# i3dPDK_A16K 4-track technology LEF (1x), derived from TECH/i3dPDK_A16K_0V7_27C_4T_mw.tf
# i3dPDK_A16K v1.0 (CC BY-NC-SA 4.0, Prof. Taigon Song, I3D VLSI Lab, KNU)
# NOT part of the original PDK. Routing directions, wire R/C and via resistance
# are placeholders (see platform/README.md).
VERSION 5.8 ;
BUSBITCHARS "[]" ;
DIVIDERCHAR "/" ;

UNITS
  DATABASE MICRONS 2000 ;
END UNITS
MANUFACTURINGGRID 0.0005 ;

# Unidirectional variant: M1 M2 M3 preferred direction only, on track (RIGHTWAYONGRIDONLY + RECTONLY).
PROPERTYDEFINITIONS
  LAYER LEF58_RIGHTWAYONGRIDONLY STRING ;
  LAYER LEF58_RECTONLY STRING ;
END PROPERTYDEFINITIONS

SITE i3d_16A
  CLASS CORE ;
  SYMMETRY Y ;
  SIZE 0.042 BY 0.072 ;
END i3d_16A

SITE i3d_16A_2H_VDD
  CLASS CORE ;
  SYMMETRY Y ;
  SIZE 0.042 BY 0.144 ;
END i3d_16A_2H_VDD

SITE i3d_16A_2H_VSS
  CLASS CORE ;
  SYMMETRY Y ;
  SIZE 0.042 BY 0.144 ;
END i3d_16A_2H_VSS

SITE i3d_16A_3H_VDD
  CLASS CORE ;
  SYMMETRY Y ;
  SIZE 0.042 BY 0.216 ;
END i3d_16A_3H_VDD

SITE i3d_16A_3H_VSS
  CLASS CORE ;
  SYMMETRY Y ;
  SIZE 0.042 BY 0.216 ;
END i3d_16A_3H_VSS

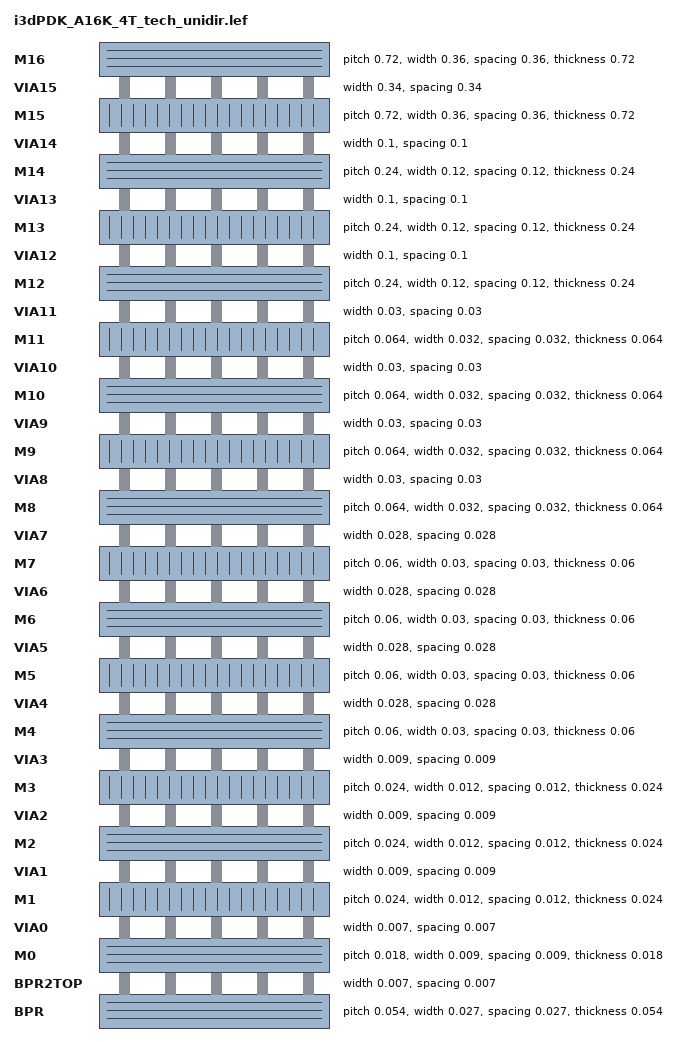
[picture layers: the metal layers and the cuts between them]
LAYER BPR
  TYPE ROUTING ;
  DIRECTION HORIZONTAL ;
  PITCH 0.054 ;
  OFFSET 0.027 ;
  WIDTH 0.027 ;
  MINWIDTH 0.027 ;
  HEIGHT 0 ;
  THICKNESS 0.054 ;
  MAXWIDTH 5 ;
  SPACING 0.027 ;
  AREA 0.003132 ;
  RESISTANCE RPERSQ 1.0000 ;
  CAPACITANCE CPERSQDIST 0.00200000 ;
  EDGECAPACITANCE 0.00008000 ;
END BPR

LAYER BPR2TOP
  TYPE CUT ;
  WIDTH 0.007 ;
  SPACING 0.007 ;
  RESISTANCE 20.0000 ;
END BPR2TOP

LAYER M0
  TYPE ROUTING ;
  DIRECTION HORIZONTAL ;
  PITCH 0.018 ;
  OFFSET 0.009 ;
  WIDTH 0.009 ;
  MINWIDTH 0.009 ;
  HEIGHT 0.108 ;
  THICKNESS 0.018 ;
  MAXWIDTH 5 ;
  SPACING 0.009 ;
  AREA 0.000081 ;
  RESISTANCE RPERSQ 8.0000 ;
  CAPACITANCE CPERSQDIST 0.00300000 ;
  EDGECAPACITANCE 0.00008000 ;
END M0

LAYER VIA0
  TYPE CUT ;
  WIDTH 0.007 ;
  SPACING 0.007 ;
  RESISTANCE 50.0000 ;
END VIA0

LAYER M1
  TYPE ROUTING ;
  DIRECTION VERTICAL ;
  PITCH 0.024 ;
  OFFSET 0 ;
  WIDTH 0.012 ;
  MINWIDTH 0.012 ;
  HEIGHT 0.144 ;
  THICKNESS 0.024 ;
  MAXWIDTH 5 ;
  SPACING 0.012 ;
  AREA 0.000144 ;
  RESISTANCE RPERSQ 8.0000 ;
  CAPACITANCE CPERSQDIST 0.00300000 ;
  EDGECAPACITANCE 0.00008000 ;
  PROPERTY LEF58_RIGHTWAYONGRIDONLY "RIGHTWAYONGRIDONLY ;" ;
  PROPERTY LEF58_RECTONLY "RECTONLY ;" ;
END M1

LAYER VIA1
  TYPE CUT ;
  WIDTH 0.009 ;
  SPACING 0.009 ;
  RESISTANCE 50.0000 ;
END VIA1

LAYER M2
  TYPE ROUTING ;
  DIRECTION HORIZONTAL ;
  PITCH 0.024 ;
  OFFSET 0 ;
  WIDTH 0.012 ;
  MINWIDTH 0.012 ;
  HEIGHT 0.192 ;
  THICKNESS 0.024 ;
  MAXWIDTH 5 ;
  SPACING 0.012 ;
  AREA 0.000144 ;
  RESISTANCE RPERSQ 8.0000 ;
  CAPACITANCE CPERSQDIST 0.00300000 ;
  EDGECAPACITANCE 0.00008000 ;
  PROPERTY LEF58_RIGHTWAYONGRIDONLY "RIGHTWAYONGRIDONLY ;" ;
  PROPERTY LEF58_RECTONLY "RECTONLY ;" ;
END M2

LAYER VIA2
  TYPE CUT ;
  WIDTH 0.009 ;
  SPACING 0.009 ;
  RESISTANCE 50.0000 ;
END VIA2

LAYER M3
  TYPE ROUTING ;
  DIRECTION VERTICAL ;
  PITCH 0.024 ;
  OFFSET 0 ;
  WIDTH 0.012 ;
  MINWIDTH 0.012 ;
  HEIGHT 0.24 ;
  THICKNESS 0.024 ;
  MAXWIDTH 5 ;
  SPACING 0.012 ;
  AREA 0.000144 ;
  RESISTANCE RPERSQ 8.0000 ;
  CAPACITANCE CPERSQDIST 0.00300000 ;
  EDGECAPACITANCE 0.00008000 ;
  PROPERTY LEF58_RIGHTWAYONGRIDONLY "RIGHTWAYONGRIDONLY ;" ;
  PROPERTY LEF58_RECTONLY "RECTONLY ;" ;
END M3

LAYER VIA3
  TYPE CUT ;
  WIDTH 0.009 ;
  SPACING 0.009 ;
  RESISTANCE 50.0000 ;
END VIA3

LAYER M4
  TYPE ROUTING ;
  DIRECTION HORIZONTAL ;
  PITCH 0.06 ;
  OFFSET 0.03 ;
  WIDTH 0.03 ;
  MINWIDTH 0.03 ;
  HEIGHT 0.288 ;
  THICKNESS 0.06 ;
  MAXWIDTH 5 ;
  SPACING 0.03 ;
  AREA 0.000900 ;
  RESISTANCE RPERSQ 1.2000 ;
  CAPACITANCE CPERSQDIST 0.00200000 ;
  EDGECAPACITANCE 0.00007000 ;
END M4

LAYER VIA4
  TYPE CUT ;
  WIDTH 0.028 ;
  SPACING 0.028 ;
  RESISTANCE 15.0000 ;
END VIA4

LAYER M5
  TYPE ROUTING ;
  DIRECTION VERTICAL ;
  PITCH 0.06 ;
  OFFSET 0.03 ;
  WIDTH 0.03 ;
  MINWIDTH 0.03 ;
  HEIGHT 0.408 ;
  THICKNESS 0.06 ;
  MAXWIDTH 5 ;
  SPACING 0.03 ;
  AREA 0.000900 ;
  RESISTANCE RPERSQ 1.2000 ;
  CAPACITANCE CPERSQDIST 0.00200000 ;
  EDGECAPACITANCE 0.00007000 ;
END M5

LAYER VIA5
  TYPE CUT ;
  WIDTH 0.028 ;
  SPACING 0.028 ;
  RESISTANCE 15.0000 ;
END VIA5

LAYER M6
  TYPE ROUTING ;
  DIRECTION HORIZONTAL ;
  PITCH 0.06 ;
  OFFSET 0.03 ;
  WIDTH 0.03 ;
  MINWIDTH 0.03 ;
  HEIGHT 0.528 ;
  THICKNESS 0.06 ;
  MAXWIDTH 5 ;
  SPACING 0.03 ;
  AREA 0.000900 ;
  RESISTANCE RPERSQ 1.2000 ;
  CAPACITANCE CPERSQDIST 0.00200000 ;
  EDGECAPACITANCE 0.00007000 ;
END M6

LAYER VIA6
  TYPE CUT ;
  WIDTH 0.028 ;
  SPACING 0.028 ;
  RESISTANCE 15.0000 ;
END VIA6

LAYER M7
  TYPE ROUTING ;
  DIRECTION VERTICAL ;
  PITCH 0.06 ;
  OFFSET 0.03 ;
  WIDTH 0.03 ;
  MINWIDTH 0.03 ;
  HEIGHT 0.648 ;
  THICKNESS 0.06 ;
  MAXWIDTH 5 ;
  SPACING 0.03 ;
  AREA 0.000900 ;
  RESISTANCE RPERSQ 1.2000 ;
  CAPACITANCE CPERSQDIST 0.00200000 ;
  EDGECAPACITANCE 0.00007000 ;
END M7

LAYER VIA7
  TYPE CUT ;
  WIDTH 0.028 ;
  SPACING 0.028 ;
  RESISTANCE 15.0000 ;
END VIA7

LAYER M8
  TYPE ROUTING ;
  DIRECTION HORIZONTAL ;
  PITCH 0.064 ;
  OFFSET 0.032 ;
  WIDTH 0.032 ;
  MINWIDTH 0.032 ;
  HEIGHT 0.768 ;
  THICKNESS 0.064 ;
  MAXWIDTH 5 ;
  SPACING 0.032 ;
  AREA 0.001024 ;
  RESISTANCE RPERSQ 1.0000 ;
  CAPACITANCE CPERSQDIST 0.00200000 ;
  EDGECAPACITANCE 0.00007000 ;
END M8

LAYER VIA8
  TYPE CUT ;
  WIDTH 0.03 ;
  SPACING 0.03 ;
  RESISTANCE 10.0000 ;
END VIA8

LAYER M9
  TYPE ROUTING ;
  DIRECTION VERTICAL ;
  PITCH 0.064 ;
  OFFSET 0.032 ;
  WIDTH 0.032 ;
  MINWIDTH 0.032 ;
  HEIGHT 0.896 ;
  THICKNESS 0.064 ;
  MAXWIDTH 5 ;
  SPACING 0.032 ;
  AREA 0.001024 ;
  RESISTANCE RPERSQ 1.0000 ;
  CAPACITANCE CPERSQDIST 0.00200000 ;
  EDGECAPACITANCE 0.00007000 ;
END M9

LAYER VIA9
  TYPE CUT ;
  WIDTH 0.03 ;
  SPACING 0.03 ;
  RESISTANCE 10.0000 ;
END VIA9

LAYER M10
  TYPE ROUTING ;
  DIRECTION HORIZONTAL ;
  PITCH 0.064 ;
  OFFSET 0.032 ;
  WIDTH 0.032 ;
  MINWIDTH 0.032 ;
  HEIGHT 1.024 ;
  THICKNESS 0.064 ;
  MAXWIDTH 5 ;
  SPACING 0.032 ;
  AREA 0.001024 ;
  RESISTANCE RPERSQ 1.0000 ;
  CAPACITANCE CPERSQDIST 0.00200000 ;
  EDGECAPACITANCE 0.00007000 ;
END M10

LAYER VIA10
  TYPE CUT ;
  WIDTH 0.03 ;
  SPACING 0.03 ;
  RESISTANCE 10.0000 ;
END VIA10

LAYER M11
  TYPE ROUTING ;
  DIRECTION VERTICAL ;
  PITCH 0.064 ;
  OFFSET 0.032 ;
  WIDTH 0.032 ;
  MINWIDTH 0.032 ;
  HEIGHT 1.152 ;
  THICKNESS 0.064 ;
  MAXWIDTH 5 ;
  SPACING 0.032 ;
  AREA 0.001024 ;
  RESISTANCE RPERSQ 1.0000 ;
  CAPACITANCE CPERSQDIST 0.00200000 ;
  EDGECAPACITANCE 0.00007000 ;
END M11

LAYER VIA11
  TYPE CUT ;
  WIDTH 0.03 ;
  SPACING 0.03 ;
  RESISTANCE 10.0000 ;
END VIA11

LAYER M12
  TYPE ROUTING ;
  DIRECTION HORIZONTAL ;
  PITCH 0.24 ;
  OFFSET 0.12 ;
  WIDTH 0.12 ;
  MINWIDTH 0.12 ;
  HEIGHT 1.28 ;
  THICKNESS 0.24 ;
  MAXWIDTH 5 ;
  SPACING 0.12 ;
  AREA 0.014400 ;
  RESISTANCE RPERSQ 0.1000 ;
  CAPACITANCE CPERSQDIST 0.00100000 ;
  EDGECAPACITANCE 0.00006000 ;
END M12

LAYER VIA12
  TYPE CUT ;
  WIDTH 0.1 ;
  SPACING 0.1 ;
  RESISTANCE 2.0000 ;
END VIA12

LAYER M13
  TYPE ROUTING ;
  DIRECTION VERTICAL ;
  PITCH 0.24 ;
  OFFSET 0.12 ;
  WIDTH 0.12 ;
  MINWIDTH 0.12 ;
  HEIGHT 1.76 ;
  THICKNESS 0.24 ;
  MAXWIDTH 5 ;
  SPACING 0.12 ;
  AREA 0.014400 ;
  RESISTANCE RPERSQ 0.1000 ;
  CAPACITANCE CPERSQDIST 0.00100000 ;
  EDGECAPACITANCE 0.00006000 ;
END M13

LAYER VIA13
  TYPE CUT ;
  WIDTH 0.1 ;
  SPACING 0.1 ;
  RESISTANCE 2.0000 ;
END VIA13

LAYER M14
  TYPE ROUTING ;
  DIRECTION HORIZONTAL ;
  PITCH 0.24 ;
  OFFSET 0.12 ;
  WIDTH 0.12 ;
  MINWIDTH 0.12 ;
  HEIGHT 2.24 ;
  THICKNESS 0.24 ;
  MAXWIDTH 5 ;
  SPACING 0.12 ;
  AREA 0.014400 ;
  RESISTANCE RPERSQ 0.1000 ;
  CAPACITANCE CPERSQDIST 0.00100000 ;
  EDGECAPACITANCE 0.00006000 ;
END M14

LAYER VIA14
  TYPE CUT ;
  WIDTH 0.1 ;
  SPACING 0.1 ;
  RESISTANCE 2.0000 ;
END VIA14

LAYER M15
  TYPE ROUTING ;
  DIRECTION VERTICAL ;
  PITCH 0.72 ;
  OFFSET 0.36 ;
  WIDTH 0.36 ;
  MINWIDTH 0.36 ;
  HEIGHT 2.72 ;
  THICKNESS 0.72 ;
  MAXWIDTH 5 ;
  SPACING 0.36 ;
  AREA 0.129600 ;
  RESISTANCE RPERSQ 0.0300 ;
  CAPACITANCE CPERSQDIST 0.00050000 ;
  EDGECAPACITANCE 0.00005000 ;
END M15

LAYER VIA15
  TYPE CUT ;
  WIDTH 0.34 ;
  SPACING 0.34 ;
  RESISTANCE 0.5000 ;
END VIA15

LAYER M16
  TYPE ROUTING ;
  DIRECTION HORIZONTAL ;
  PITCH 0.72 ;
  OFFSET 0.36 ;
  WIDTH 0.36 ;
  MINWIDTH 0.36 ;
  HEIGHT 4.16 ;
  THICKNESS 0.72 ;
  MAXWIDTH 5 ;
  SPACING 0.36 ;
  AREA 0.129600 ;
  RESISTANCE RPERSQ 0.0300 ;
  CAPACITANCE CPERSQDIST 0.00050000 ;
  EDGECAPACITANCE 0.00005000 ;
END M16

VIA viaBPR0 DEFAULT
  RESISTANCE 20.0000 ;
  LAYER BPR ;
    RECT -0.0135 -0.0135 0.0135 0.0135 ;
  LAYER BPR2TOP ;
    RECT -0.0035 -0.0035 0.0035 0.0035 ;
  LAYER M0 ;
    RECT -0.0045 -0.0045 0.0045 0.0045 ;
END viaBPR0

VIA via01 DEFAULT
  RESISTANCE 50.0000 ;
  LAYER M0 ;
    RECT -0.0045 -0.0045 0.0045 0.0045 ;
  LAYER VIA0 ;
    RECT -0.0035 -0.0035 0.0035 0.0035 ;
  LAYER M1 ;
    RECT -0.006 -0.006 0.006 0.006 ;
END via01

VIA via12 DEFAULT
  RESISTANCE 50.0000 ;
  LAYER M1 ;
    RECT -0.006 -0.006 0.006 0.006 ;
  LAYER VIA1 ;
    RECT -0.0045 -0.0045 0.0045 0.0045 ;
  LAYER M2 ;
    RECT -0.006 -0.006 0.006 0.006 ;
END via12

VIA via23 DEFAULT
  RESISTANCE 50.0000 ;
  LAYER M2 ;
    RECT -0.006 -0.006 0.006 0.006 ;
  LAYER VIA2 ;
    RECT -0.0045 -0.0045 0.0045 0.0045 ;
  LAYER M3 ;
    RECT -0.006 -0.006 0.006 0.006 ;
END via23

VIA via34 DEFAULT
  RESISTANCE 50.0000 ;
  LAYER M3 ;
    RECT -0.007 -0.007 0.007 0.007 ;
  LAYER VIA3 ;
    RECT -0.007 -0.007 0.007 0.007 ;
  LAYER M4 ;
    RECT -0.015 -0.015 0.015 0.015 ;
END via34

VIA via45 DEFAULT
  RESISTANCE 15.0000 ;
  LAYER M4 ;
    RECT -0.015 -0.015 0.015 0.015 ;
  LAYER VIA4 ;
    RECT -0.015 -0.015 0.015 0.015 ;
  LAYER M5 ;
    RECT -0.015 -0.015 0.015 0.015 ;
END via45

VIA via56 DEFAULT
  RESISTANCE 15.0000 ;
  LAYER M5 ;
    RECT -0.015 -0.015 0.015 0.015 ;
  LAYER VIA5 ;
    RECT -0.015 -0.015 0.015 0.015 ;
  LAYER M6 ;
    RECT -0.015 -0.015 0.015 0.015 ;
END via56

VIA via67 DEFAULT
  RESISTANCE 15.0000 ;
  LAYER M6 ;
    RECT -0.015 -0.015 0.015 0.015 ;
  LAYER VIA6 ;
    RECT -0.015 -0.015 0.015 0.015 ;
  LAYER M7 ;
    RECT -0.015 -0.015 0.015 0.015 ;
END via67

VIA via78 DEFAULT
  RESISTANCE 15.0000 ;
  LAYER M7 ;
    RECT -0.015 -0.015 0.015 0.015 ;
  LAYER VIA7 ;
    RECT -0.015 -0.015 0.015 0.015 ;
  LAYER M8 ;
    RECT -0.016 -0.016 0.016 0.016 ;
END via78

VIA via89 DEFAULT
  RESISTANCE 10.0000 ;
  LAYER M8 ;
    RECT -0.016 -0.016 0.016 0.016 ;
  LAYER VIA8 ;
    RECT -0.016 -0.016 0.016 0.016 ;
  LAYER M9 ;
    RECT -0.016 -0.016 0.016 0.016 ;
END via89

VIA via910 DEFAULT
  RESISTANCE 10.0000 ;
  LAYER M9 ;
    RECT -0.016 -0.016 0.016 0.016 ;
  LAYER VIA9 ;
    RECT -0.016 -0.016 0.016 0.016 ;
  LAYER M10 ;
    RECT -0.016 -0.016 0.016 0.016 ;
END via910

VIA via1011 DEFAULT
  RESISTANCE 10.0000 ;
  LAYER M10 ;
    RECT -0.016 -0.016 0.016 0.016 ;
  LAYER VIA10 ;
    RECT -0.016 -0.016 0.016 0.016 ;
  LAYER M11 ;
    RECT -0.016 -0.016 0.016 0.016 ;
END via1011

VIA via1112 DEFAULT
  RESISTANCE 10.0000 ;
  LAYER M11 ;
    RECT -0.016 -0.016 0.016 0.016 ;
  LAYER VIA11 ;
    RECT -0.016 -0.016 0.016 0.016 ;
  LAYER M12 ;
    RECT -0.06 -0.06 0.06 0.06 ;
END via1112

VIA via1213 DEFAULT
  RESISTANCE 2.0000 ;
  LAYER M12 ;
    RECT -0.06 -0.06 0.06 0.06 ;
  LAYER VIA12 ;
    RECT -0.018 -0.018 0.018 0.018 ;
  LAYER M13 ;
    RECT -0.06 -0.06 0.06 0.06 ;
END via1213

VIA via1314 DEFAULT
  RESISTANCE 2.0000 ;
  LAYER M13 ;
    RECT -0.06 -0.06 0.06 0.06 ;
  LAYER VIA13 ;
    RECT -0.018 -0.018 0.018 0.018 ;
  LAYER M14 ;
    RECT -0.06 -0.06 0.06 0.06 ;
END via1314

VIA via1415 DEFAULT
  RESISTANCE 2.0000 ;
  LAYER M14 ;
    RECT -0.06 -0.06 0.06 0.06 ;
  LAYER VIA14 ;
    RECT -0.018 -0.018 0.018 0.018 ;
  LAYER M15 ;
    RECT -0.18 -0.18 0.18 0.18 ;
END via1415

VIA via1516 DEFAULT
  RESISTANCE 0.5000 ;
  LAYER M15 ;
    RECT -0.18 -0.18 0.18 0.18 ;
  LAYER VIA15 ;
    RECT -0.018 -0.018 0.018 0.018 ;
  LAYER M16 ;
    RECT -0.18 -0.18 0.18 0.18 ;
END via1516

VIARULE viaBPR0_gen GENERATE
  LAYER BPR ;
    ENCLOSURE 0 0 ;
  LAYER M0 ;
    ENCLOSURE 0 0 ;
  LAYER BPR2TOP ;
    RECT -0.0035 -0.0035 0.0035 0.0035 ;
    SPACING 0.014 BY 0.014 ;
END viaBPR0_gen

VIARULE via01_gen GENERATE
  LAYER M0 ;
    ENCLOSURE 0 0 ;
  LAYER M1 ;
    ENCLOSURE 0 0 ;
  LAYER VIA0 ;
    RECT -0.0035 -0.0035 0.0035 0.0035 ;
    SPACING 0.014 BY 0.014 ;
END via01_gen

VIARULE via12_gen GENERATE
  LAYER M1 ;
    ENCLOSURE 0 0 ;
  LAYER M2 ;
    ENCLOSURE 0 0 ;
  LAYER VIA1 ;
    RECT -0.0045 -0.0045 0.0045 0.0045 ;
    SPACING 0.018 BY 0.018 ;
END via12_gen

VIARULE via23_gen GENERATE
  LAYER M2 ;
    ENCLOSURE 0 0 ;
  LAYER M3 ;
    ENCLOSURE 0 0 ;
  LAYER VIA2 ;
    RECT -0.0045 -0.0045 0.0045 0.0045 ;
    SPACING 0.018 BY 0.018 ;
END via23_gen

VIARULE via34_gen GENERATE
  LAYER M3 ;
    ENCLOSURE 0 0 ;
  LAYER M4 ;
    ENCLOSURE 0 0 ;
  LAYER VIA3 ;
    RECT -0.007 -0.007 0.007 0.007 ;
    SPACING 0.028 BY 0.028 ;
END via34_gen

VIARULE via45_gen GENERATE
  LAYER M4 ;
    ENCLOSURE 0 0 ;
  LAYER M5 ;
    ENCLOSURE 0 0 ;
  LAYER VIA4 ;
    RECT -0.015 -0.015 0.015 0.015 ;
    SPACING 0.06 BY 0.06 ;
END via45_gen

VIARULE via56_gen GENERATE
  LAYER M5 ;
    ENCLOSURE 0 0 ;
  LAYER M6 ;
    ENCLOSURE 0 0 ;
  LAYER VIA5 ;
    RECT -0.015 -0.015 0.015 0.015 ;
    SPACING 0.06 BY 0.06 ;
END via56_gen

VIARULE via67_gen GENERATE
  LAYER M6 ;
    ENCLOSURE 0 0 ;
  LAYER M7 ;
    ENCLOSURE 0 0 ;
  LAYER VIA6 ;
    RECT -0.015 -0.015 0.015 0.015 ;
    SPACING 0.06 BY 0.06 ;
END via67_gen

VIARULE via78_gen GENERATE
  LAYER M7 ;
    ENCLOSURE 0 0 ;
  LAYER M8 ;
    ENCLOSURE 0 0 ;
  LAYER VIA7 ;
    RECT -0.015 -0.015 0.015 0.015 ;
    SPACING 0.06 BY 0.06 ;
END via78_gen

VIARULE via89_gen GENERATE
  LAYER M8 ;
    ENCLOSURE 0 0 ;
  LAYER M9 ;
    ENCLOSURE 0 0 ;
  LAYER VIA8 ;
    RECT -0.016 -0.016 0.016 0.016 ;
    SPACING 0.064 BY 0.064 ;
END via89_gen

VIARULE via910_gen GENERATE
  LAYER M9 ;
    ENCLOSURE 0 0 ;
  LAYER M10 ;
    ENCLOSURE 0 0 ;
  LAYER VIA9 ;
    RECT -0.016 -0.016 0.016 0.016 ;
    SPACING 0.064 BY 0.064 ;
END via910_gen

VIARULE via1011_gen GENERATE
  LAYER M10 ;
    ENCLOSURE 0 0 ;
  LAYER M11 ;
    ENCLOSURE 0 0 ;
  LAYER VIA10 ;
    RECT -0.016 -0.016 0.016 0.016 ;
    SPACING 0.064 BY 0.064 ;
END via1011_gen

VIARULE via1112_gen GENERATE
  LAYER M11 ;
    ENCLOSURE 0 0 ;
  LAYER M12 ;
    ENCLOSURE 0 0 ;
  LAYER VIA11 ;
    RECT -0.016 -0.016 0.016 0.016 ;
    SPACING 0.064 BY 0.064 ;
END via1112_gen

VIARULE via1213_gen GENERATE
  LAYER M12 ;
    ENCLOSURE 0 0 ;
  LAYER M13 ;
    ENCLOSURE 0 0 ;
  LAYER VIA12 ;
    RECT -0.018 -0.018 0.018 0.018 ;
    SPACING 0.072 BY 0.072 ;
END via1213_gen

VIARULE via1314_gen GENERATE
  LAYER M13 ;
    ENCLOSURE 0 0 ;
  LAYER M14 ;
    ENCLOSURE 0 0 ;
  LAYER VIA13 ;
    RECT -0.018 -0.018 0.018 0.018 ;
    SPACING 0.072 BY 0.072 ;
END via1314_gen

VIARULE via1415_gen GENERATE
  LAYER M14 ;
    ENCLOSURE 0 0 ;
  LAYER M15 ;
    ENCLOSURE 0 0 ;
  LAYER VIA14 ;
    RECT -0.018 -0.018 0.018 0.018 ;
    SPACING 0.072 BY 0.072 ;
END via1415_gen

VIARULE via1516_gen GENERATE
  LAYER M15 ;
    ENCLOSURE 0 0 ;
  LAYER M16 ;
    ENCLOSURE 0 0 ;
  LAYER VIA15 ;
    RECT -0.018 -0.018 0.018 0.018 ;
    SPACING 0.072 BY 0.072 ;
END via1516_gen

END LIBRARY
